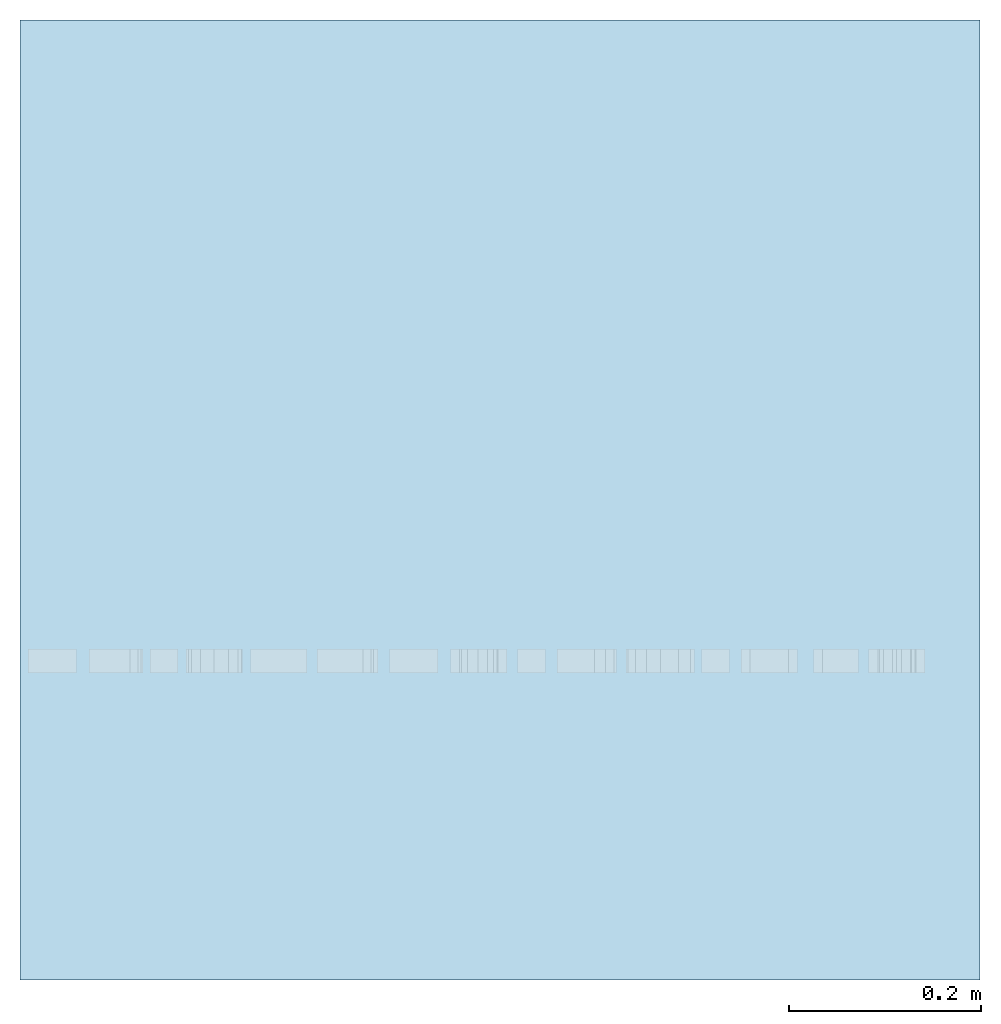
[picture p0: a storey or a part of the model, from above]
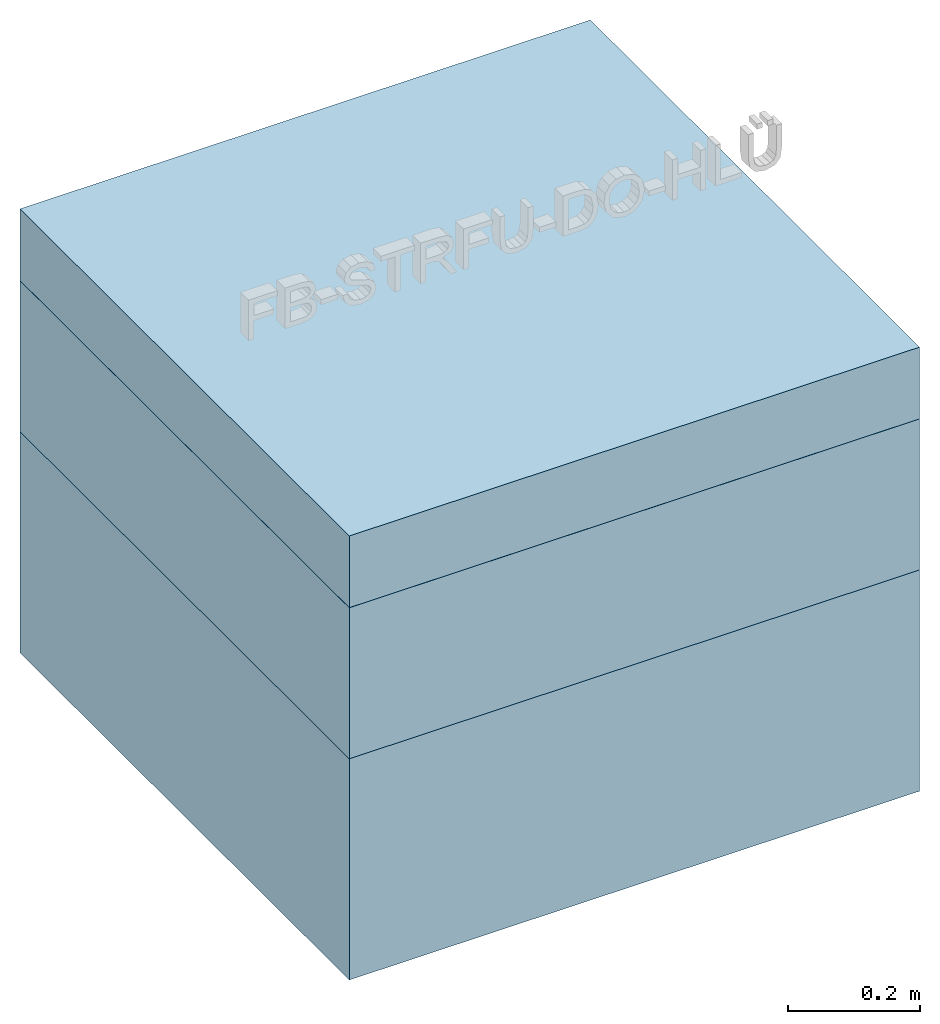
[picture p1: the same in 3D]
Properties of the parts of a building model (IFC4)

# File
Description: ViewDefinition [ReferenceView_V1.2], RevitIdentifiers [VersionGUID: 25224f80-5d8e-4640-b9d8-b88f8e84a847, NumberOfSaves: 3], CoordinateReference [CoordinateBase: Gemeinsam genutzte Koordinaten], ExchangeRequirement [Architecture]
File name: 2018_01
Time: 2023-07-05T12:00:00+01:00
Written by: ODA SDAI 23.12
Made in: Autodesk Revit 24.0.5.432 (DEU) - IFC 24.0.5.432

# IfcProject, 2018_01
Phase: Projekt Status

# IfcSite, Default
RefLatitude: 48, 8, 15, 359802; RefLongitude: 11, 34, 47, 783432; RefElevation: 0 m
Pset_SiteCommon - Reference: Projektinformationen

# IfcBuildingElementProxy: Modelltext:075mm Arial, Modelltext:075mm Arial:2510666
In: Default
Type - Pset_BuildingElementProxyCommon - IsExternal: no
Pset_BuildingElementProxyCommon - Reference: 075mm Arial
Pset_EnvironmentalImpactIndicators - Reference: 075mm Arial
Qto_BuildingElementProxyQuantities - NetSurfaceArea: 0.161583 m2; NetVolume: 0.000529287 m3

# IfcElementAssembly: Geschossdecken Baugruppe:fbimSg_Slab_bc_WOD_vis_at_NTR_natuREbuilt_FB-STRFU-DO-HLÜ_GK3_82cm, Geschossdecken Baugruppe:fbimSg_Slab_bc_WOD_vis_at_NTR_natuREbuilt_FB-STRFU-DO-HLÜ_GK3_82cm:2510688
In: Default
PredefinedType: USERDEFINED; Material: fbim_18108010_AT_015_Parkettboden, fbim_16053507_AT_Trockenestrich_gips, fbim_14104055_AT_040_HF-Trittschalldaemmplatte, fbim_12401520_AT_OSB, fbim_14100500_at_NTR_Zellulose-Einblasdaemmung
Pset_ElementAssemblyCommon - Reference: fbimSg_Slab_bc_WOD_vis_at_NTR_natuREbuilt_FB-STRFU-DO-HLÜ_GK3_82cm; sets with these values: 2

# IfcSlab: Geschossdecke:fbimSg_Floor_dp_AIR_vis_at_NTR_natuREbuilt_FBhZS_GK3_u_40cm, Geschossdecke:fbimSg_Floor_dp_AIR_vis_at_NTR_natuREbuilt_FBhZS_GK3_u_40cm:2510683
In: Default
Type - PredefinedType: FLOOR; Material: fbim_12401505_at_NTR_Holz_Spanplatte_1cm, fbim_14100590_AT_001_Luftschicht
Type - Pset_SlabCommon - IsExternal: no
Pset_EnvironmentalImpactIndicators - Reference: fbimSg_Floor_dp_AIR_vis_at_NTR_natuREbuilt_FBhZS_GK3_u_40cm; sets with these values: 2
Pset_SlabCommon - PitchAngle: 0 deg; LoadBearing: no; Reference: fbimSg_Floor_dp_AIR_vis_at_NTR_natuREbuilt_FBhZS_GK3_u_40cm
Qto_SlabBaseQuantities - fbim_12401505_at_NTR_Holz_Spanplatte_1cm, Width: 0.01 m; fbim_14100590_AT_001_Luftschicht, Width: 0.4 m; Width: 0.41 m; Length: 1 m; Depth: 0.4 m; Perimeter: 4 m; GrossArea: 1 m2; GrossVolume: 0.4 m3; NetVolume: 0.41 m3

# IfcSlab: Geschossdecke:fbimSg_Slab_sb_INS_vis_at_NTR_natuREbuilt_FBhZS_GK3_o_13,5cm, Geschossdecke:fbimSg_Slab_sb_INS_vis_at_NTR_natuREbuilt_FBhZS_GK3_o_13,5cm:2510669
In: Default
Type - PredefinedType: FLOOR; Material: fbim_18108010_AT_015_Parkettboden, fbim_16053507_AT_Trockenestrich_gips, fbim_14104055_AT_040_HF-Trittschalldaemmplatte, fbim_12401520_AT_OSB, fbim_14100500_at_NTR_Zellulose-Einblasdaemmung
Type - Pset_SlabCommon - IsExternal: no
Pset_EnvironmentalImpactIndicators - Reference: fbimSg_Slab_sb_INS_vis_at_NTR_natuREbuilt_FBhZS_GK3_o_13,5cm; sets with these values: 2
Pset_SlabCommon - Reference: fbimSg_Slab_sb_INS_vis_at_NTR_natuREbuilt_FBhZS_GK3_o_13,5cm; PitchAngle: 0 deg; LoadBearing: no
Qto_SlabBaseQuantities - fbim_18108010_AT_015_Parkettboden, Width: 0.015 m; fbim_16053507_AT_Trockenestrich_gips, Width: 0.02 m; fbim_14104055_AT_040_HF-Trittschalldaemmplatte, Width: 0.02 m; fbim_12401520_AT_OSB, Width: 0.018 m; fbim_14100500_at_NTR_Zellulose-Einblasdaemmung, Width: 0.06 m; Width: 0.133 m; Length: 1 m; Depth: 0.06 m; Perimeter: 4 m; GrossArea: 1 m2; GrossVolume: 0.06 m3; NetVolume: 0.133 m3

# IfcSlab: Geschossdecke:fbimSg_Slab_sb_WOD_vis_at_NTR_natuREbuilt_FBhZS_GK3_k_28cm, Geschossdecke:fbimSg_Slab_sb_WOD_vis_at_NTR_natuREbuilt_FBhZS_GK3_k_28cm:2510676
In: Default
Type - PredefinedType: FLOOR; Material: fbim_14100500_at_NTR_Zellulose-Einblasdaemmung
Type - Pset_SlabCommon - IsExternal: no
Pset_EnvironmentalImpactIndicators - Reference: fbimSg_Slab_sb_WOD_vis_at_NTR_natuREbuilt_FBhZS_GK3_k_28cm; sets with these values: 2
Pset_SlabCommon - PitchAngle: 0 deg; LoadBearing: no; Reference: fbimSg_Slab_sb_WOD_vis_at_NTR_natuREbuilt_FBhZS_GK3_k_28cm
Qto_SlabBaseQuantities - Width: 1 m; Length: 1 m; Depth: 0.28 m; Perimeter: 4 m; GrossArea: 1 m2; GrossVolume: 0.28 m3; NetVolume: 0.28 m3
